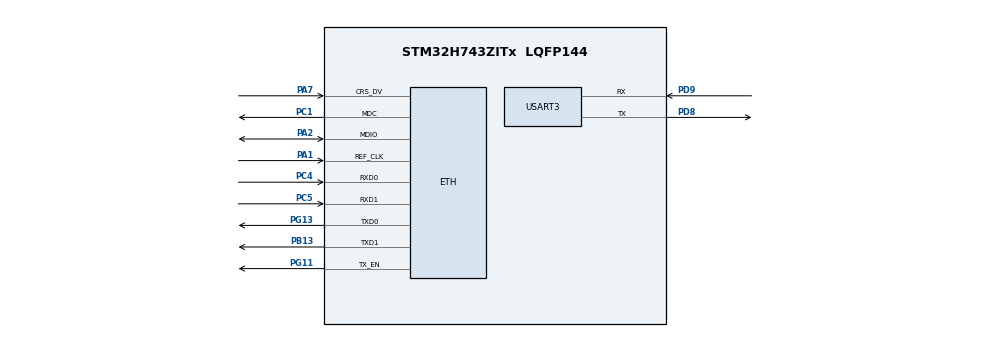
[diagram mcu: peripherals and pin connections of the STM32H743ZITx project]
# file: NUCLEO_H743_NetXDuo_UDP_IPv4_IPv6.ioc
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CORTEX_M7.AccessPermission_S-Cortex_Memory_Protection_Unit_Region1_Settings_S=MPU_REGION_FULL_ACCESS
CORTEX_M7.BaseAddress_S-Cortex_Memory_Protection_Unit_Region1_Settings_S=0x30040000
CORTEX_M7.CPU_DCache=Enabled
CORTEX_M7.CPU_ICache=Enabled
CORTEX_M7.DisableExec_S-Cortex_Memory_Protection_Unit_Region1_Settings_S=MPU_INSTRUCTION_ACCESS_DISABLE
CORTEX_M7.Enable_S-Cortex_Memory_Protection_Unit_Region1_Settings_S=MPU_REGION_ENABLE
CORTEX_M7.Size_S-Cortex_Memory_Protection_Unit_Region1_Settings_S=MPU_REGION_SIZE_128KB
CORTEX_M7.TypeExtField_S-Cortex_Memory_Protection_Unit_Region1_Settings_S=MPU_TEX_LEVEL1
CORTEX_M7.default_mode_Activation=1
ETH.MediaInterface=HAL_ETH_RMII_MODE
ETH.RxDescAddress=0x30040000
ETH.TxDescAddress=0x30040060
Mcu.Family=STM32H7
Mcu.Name=STM32H743ZITx
Mcu.Package=LQFP144
NVIC.ETH_IRQn=true\:0\:0\:false\:false\:true\:false\:true\:true\:true
NVIC.PriorityGroup=NVIC_PRIORITYGROUP_4
NVIC.TIM6_DAC_IRQn=true\:15\:0\:false\:false\:true\:false\:false\:true\:true
NVIC.TimeBase=TIM6_DAC_IRQn
NVIC.TimeBaseIP=TIM6
PA1.GPIO_Speed=GPIO_SPEED_FREQ_VERY_HIGH
PA1.Mode=RMII
PA1.Signal=ETH_REF_CLK
PA2.GPIO_Speed=GPIO_SPEED_FREQ_VERY_HIGH
PA2.Mode=RMII
PA2.Signal=ETH_MDIO
PA7.GPIO_Speed=GPIO_SPEED_FREQ_VERY_HIGH
PA7.Mode=RMII
PA7.Signal=ETH_CRS_DV
PB13.GPIO_Speed=GPIO_SPEED_FREQ_VERY_HIGH
PB13.Mode=RMII
PB13.Signal=ETH_TXD1
PC1.GPIO_Speed=GPIO_SPEED_FREQ_VERY_HIGH
PC1.Mode=RMII
PC1.Signal=ETH_MDC
PC4.GPIO_Speed=GPIO_SPEED_FREQ_VERY_HIGH
PC4.Mode=RMII
PC4.Signal=ETH_RXD0
PC5.GPIO_Speed=GPIO_SPEED_FREQ_VERY_HIGH
PC5.Mode=RMII
PC5.Signal=ETH_RXD1
PD8.Mode=Asynchronous
PD8.Signal=USART3_TX
PD9.Mode=Asynchronous
PD9.Signal=USART3_RX
PG11.GPIO_Speed=GPIO_SPEED_FREQ_VERY_HIGH
PG11.Mode=RMII
PG11.Signal=ETH_TX_EN
PG13.GPIO_Speed=GPIO_SPEED_FREQ_VERY_HIGH
PG13.Mode=RMII
PG13.Signal=ETH_TXD0
PH0-OSC_IN\ (PH0).Mode=HSE-External-Clock-Source
PH0-OSC_IN\ (PH0).Signal=RCC_OSC_IN
ProjectManager.HeapSize=0x200
ProjectManager.StackSize=0x400
ProjectManager.TargetToolchain=STM32CubeIDE
RCC.ADCFreq_Value=16125000
RCC.APB1Freq_Value=100000000
RCC.APB2Freq_Value=100000000
RCC.APB3Freq_Value=100000000
RCC.APB4Freq_Value=100000000
RCC.CortexFreq_Value=400000000
RCC.D1PPRE=RCC_APB3_DIV2
RCC.D2PPRE1=RCC_APB1_DIV2
RCC.D2PPRE2=RCC_APB2_DIV2
RCC.D3PPRE=RCC_APB4_DIV2
RCC.DIVM1=1
RCC.DIVN1=100
RCC.HCLKFreq_Value=200000000
RCC.HPRE=RCC_HCLK_DIV2
RCC.HSE_VALUE=8000000
RCC.PLLFRACN=0
RCC.PLLSourceVirtual=RCC_PLLSOURCE_HSE
RCC.PWR_Regulator_Voltage_Scale=PWR_REGULATOR_VOLTAGE_SCALE1
RCC.SYSCLKFreq_VALUE=400000000
RCC.SYSCLKSource=RCC_SYSCLKSOURCE_PLLCLK
RCC.USBFreq_Value=400000000
STMicroelectronics.X-CUBE-AZRTOS-H7.3.1.0.FEATURE_NX_IPV6=true
STMicroelectronics.X-CUBE-AZRTOS-H7.3.1.0.InterfacesCcNetworkJjEthernetOoInterface=true
STMicroelectronics.X-CUBE-AZRTOS-H7.3.1.0.InterfacesCcNetworkJjEthernetOoPhyOoInterface=LAN8742IiPhyIiInterface
STMicroelectronics.X-CUBE-AZRTOS-H7.3.1.0.NX_APP_IP_INSTANCE_THREAD_SIZE=2*1024
STMicroelectronics.X-CUBE-AZRTOS-H7.3.1.0.NX_APP_MEM_POOL_SIZE=30*1024
STMicroelectronics.X-CUBE-AZRTOS-H7.3.1.0.NX_APP_PACKET_POOL_SIZE=10
STMicroelectronics.X-CUBE-AZRTOS-H7.3.1.0.NX_APP_THREAD_STACK_SIZE=2*1024
STMicroelectronics.X-CUBE-AZRTOS-H7.3.1.0.NetXDuoCcNetworkJjNetXDuoJjNXOoCore=true
STMicroelectronics.X-CUBE-AZRTOS-H7.3.1.0.NetXDuo_Static_IP_address=192.168.1.111
STMicroelectronics.X-CUBE-AZRTOS-H7.3.1.0.STM32CubeIiBSPIiComponentsCcBoardOoPartJjETHPhyJjLAN8742=true
STMicroelectronics.X-CUBE-AZRTOS-H7.3.1.0.ThreadXCcRTOSJjThreadXJjCore=true
STMicroelectronics.X-CUBE-AZRTOS-H7.3.1.0_IsAnAzureRtosMw=true
USART3.VirtualMode-Asynchronous=VM_ASYNC
VP_STMicroelectronics.X-CUBE-AZRTOS-H7_VS_BoardOoPartJjSTM32CubeIiBSPIiComponents_1.1.0_3.1.0.Mode=BoardOoPartJjSTM32CubeIiBSPIiComponents
VP_STMicroelectronics.X-CUBE-AZRTOS-H7_VS_NetworkJjInterfaces_2.1.0_3.1.0.Mode=NetworkJjInterfaces
VP_STMicroelectronics.X-CUBE-AZRTOS-H7_VS_NetworkJjNetXDuo_6.2.0_3.1.0.Mode=NetworkJjNetXDuo
VP_STMicroelectronics.X-CUBE-AZRTOS-H7_VS_RTOSJjThreadX_6.2.0_3.1.0.Mode=RTOSJjThreadX
VP_SYS_VS_tim6.Mode=TIM6
board=NUCLEO-H743ZI2

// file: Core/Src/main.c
/* USER CODE BEGIN Header */
/**
  ******************************************************************************
  * @file           : main.c
  * @brief          : Main program body
  ******************************************************************************
  * @attention
  *
  * Copyright (c) 2023 STMicroelectronics.
  * All rights reserved.
  *
  * This software is licensed under terms that can be found in the LICENSE file
  * in the root directory of this software component.
  * If no LICENSE file comes with this software, it is provided AS-IS.
  *
  ******************************************************************************
  */
/* USER CODE END Header */
#include "app_threadx.h"
#include "main.h"
#include "string.h"

#if defined ( __ICCARM__ ) /*!< IAR Compiler */
#pragma location=0x30040000
ETH_DMADescTypeDef  DMARxDscrTab[ETH_RX_DESC_CNT]; /* Ethernet Rx DMA Descriptors */
#pragma location=0x30040060
ETH_DMADescTypeDef  DMATxDscrTab[ETH_TX_DESC_CNT]; /* Ethernet Tx DMA Descriptors */

#elif defined ( __CC_ARM )  /* MDK ARM Compiler */

__attribute__((at(0x30040000))) ETH_DMADescTypeDef  DMARxDscrTab[ETH_RX_DESC_CNT]; /* Ethernet Rx DMA Descriptors */
__attribute__((at(0x30040060))) ETH_DMADescTypeDef  DMATxDscrTab[ETH_TX_DESC_CNT]; /* Ethernet Tx DMA Descriptors */

#elif defined ( __GNUC__ ) /* GNU Compiler */
ETH_DMADescTypeDef DMARxDscrTab[ETH_RX_DESC_CNT] __attribute__((section(".RxDecripSection"))); /* Ethernet Rx DMA Descriptors */
ETH_DMADescTypeDef DMATxDscrTab[ETH_TX_DESC_CNT] __attribute__((section(".TxDecripSection")));   /* Ethernet Tx DMA Descriptors */

#endif

ETH_TxPacketConfig TxConfig;

ETH_HandleTypeDef heth;

UART_HandleTypeDef huart3;

void SystemClock_Config(void);
static void MPU_Config(void);
static void MX_GPIO_Init(void);
static void MX_ETH_Init(void);
static void MX_USART3_UART_Init(void);

/* USER CODE BEGIN 0 */

int __io_putchar(int ch)
{
  /* Place your implementation of fputc here */
  /* e.g. write a character to the USART1 and Loop until the end of transmission */
  HAL_UART_Transmit(&huart3, (uint8_t *)&ch, 1, 0xFFFF);

  return ch;
}

/* USER CODE END 0 */

int main(void)
{

  /* MPU Configuration--------------------------------------------------------*/
  MPU_Config();

  /* Enable I-Cache---------------------------------------------------------*/
  SCB_EnableICache();

  /* Enable D-Cache---------------------------------------------------------*/
  SCB_EnableDCache();

  /* MCU Configuration--------------------------------------------------------*/

  /* Reset of all peripherals, Initializes the Flash interface and the Systick. */
  HAL_Init();

  /* Configure the system clock */
  SystemClock_Config();

  /* Initialize all configured peripherals */
  MX_GPIO_Init();
  MX_ETH_Init();
  MX_USART3_UART_Init();

  MX_ThreadX_Init();

  /* We should never get here as control is now taken by the scheduler */
  /* Infinite loop */
  while (1)
  {

  }
}

void SystemClock_Config(void)
{
  RCC_OscInitTypeDef RCC_OscInitStruct = {0};
  RCC_ClkInitTypeDef RCC_ClkInitStruct = {0};

  /** Supply configuration update enable
  */
  HAL_PWREx_ConfigSupply(PWR_LDO_SUPPLY);

  /** Configure the main internal regulator output voltage
  */
  __HAL_PWR_VOLTAGESCALING_CONFIG(PWR_REGULATOR_VOLTAGE_SCALE1);

  while(!__HAL_PWR_GET_FLAG(PWR_FLAG_VOSRDY)) {}

  /** Initializes the RCC Oscillators according to the specified parameters
  * in the RCC_OscInitTypeDef structure.
  */
  RCC_OscInitStruct.OscillatorType = RCC_OSCILLATORTYPE_HSE;
  RCC_OscInitStruct.HSEState = RCC_HSE_BYPASS;
  RCC_OscInitStruct.PLL.PLLState = RCC_PLL_ON;
  RCC_OscInitStruct.PLL.PLLSource = RCC_PLLSOURCE_HSE;
  RCC_OscInitStruct.PLL.PLLM = 1;
  RCC_OscInitStruct.PLL.PLLN = 100;
  RCC_OscInitStruct.PLL.PLLP = 2;
  RCC_OscInitStruct.PLL.PLLQ = 2;
  RCC_OscInitStruct.PLL.PLLR = 2;
  RCC_OscInitStruct.PLL.PLLRGE = RCC_PLL1VCIRANGE_3;
  RCC_OscInitStruct.PLL.PLLVCOSEL = RCC_PLL1VCOWIDE;
  RCC_OscInitStruct.PLL.PLLFRACN = 0;
  if (HAL_RCC_OscConfig(&RCC_OscInitStruct) != HAL_OK)
  {
    Error_Handler();
  }

  /** Initializes the CPU, AHB and APB buses clocks
  */
  RCC_ClkInitStruct.ClockType = RCC_CLOCKTYPE_HCLK|RCC_CLOCKTYPE_SYSCLK
                              |RCC_CLOCKTYPE_PCLK1|RCC_CLOCKTYPE_PCLK2
                              |RCC_CLOCKTYPE_D3PCLK1|RCC_CLOCKTYPE_D1PCLK1;
  RCC_ClkInitStruct.SYSCLKSource = RCC_SYSCLKSOURCE_PLLCLK;
  RCC_ClkInitStruct.SYSCLKDivider = RCC_SYSCLK_DIV1;
  RCC_ClkInitStruct.AHBCLKDivider = RCC_HCLK_DIV2;
  RCC_ClkInitStruct.APB3CLKDivider = RCC_APB3_DIV2;
  RCC_ClkInitStruct.APB1CLKDivider = RCC_APB1_DIV2;
  RCC_ClkInitStruct.APB2CLKDivider = RCC_APB2_DIV2;
  RCC_ClkInitStruct.APB4CLKDivider = RCC_APB4_DIV2;

  if (HAL_RCC_ClockConfig(&RCC_ClkInitStruct, FLASH_LATENCY_2) != HAL_OK)
  {
    Error_Handler();
  }
}

static void MX_ETH_Init(void)
{

   static uint8_t MACAddr[6];

  heth.Instance = ETH;
  MACAddr[0] = 0x00;
  MACAddr[1] = 0x80;
  MACAddr[2] = 0xE1;
  MACAddr[3] = 0x00;
  MACAddr[4] = 0x00;
  MACAddr[5] = 0x00;
  heth.Init.MACAddr = &MACAddr[0];
  heth.Init.MediaInterface = HAL_ETH_RMII_MODE;
  heth.Init.TxDesc = DMATxDscrTab;
  heth.Init.RxDesc = DMARxDscrTab;
  heth.Init.RxBuffLen = 1536;

  if (HAL_ETH_Init(&heth) != HAL_OK)
  {
    Error_Handler();
  }

  memset(&TxConfig, 0 , sizeof(ETH_TxPacketConfig));
  TxConfig.Attributes = ETH_TX_PACKETS_FEATURES_CSUM | ETH_TX_PACKETS_FEATURES_CRCPAD;
  TxConfig.ChecksumCtrl = ETH_CHECKSUM_IPHDR_PAYLOAD_INSERT_PHDR_CALC;
  TxConfig.CRCPadCtrl = ETH_CRC_PAD_INSERT;

}

static void MX_USART3_UART_Init(void)
{

  huart3.Instance = USART3;
  huart3.Init.BaudRate = 115200;
  huart3.Init.WordLength = UART_WORDLENGTH_8B;
  huart3.Init.StopBits = UART_STOPBITS_1;
  huart3.Init.Parity = UART_PARITY_NONE;
  huart3.Init.Mode = UART_MODE_TX_RX;
  huart3.Init.HwFlowCtl = UART_HWCONTROL_NONE;
  huart3.Init.OverSampling = UART_OVERSAMPLING_16;
  huart3.Init.OneBitSampling = UART_ONE_BIT_SAMPLE_DISABLE;
  huart3.Init.ClockPrescaler = UART_PRESCALER_DIV1;
  huart3.AdvancedInit.AdvFeatureInit = UART_ADVFEATURE_NO_INIT;
  if (HAL_UART_Init(&huart3) != HAL_OK)
  {
    Error_Handler();
  }
  if (HAL_UARTEx_SetTxFifoThreshold(&huart3, UART_TXFIFO_THRESHOLD_1_8) != HAL_OK)
  {
    Error_Handler();
  }
  if (HAL_UARTEx_SetRxFifoThreshold(&huart3, UART_RXFIFO_THRESHOLD_1_8) != HAL_OK)
  {
    Error_Handler();
  }
  if (HAL_UARTEx_DisableFifoMode(&huart3) != HAL_OK)
  {
    Error_Handler();
  }

}

static void MX_GPIO_Init(void)
{
  GPIO_InitTypeDef GPIO_InitStruct = {0};

  /* GPIO Ports Clock Enable */
  __HAL_RCC_GPIOH_CLK_ENABLE();
  __HAL_RCC_GPIOC_CLK_ENABLE();
  __HAL_RCC_GPIOA_CLK_ENABLE();
  __HAL_RCC_GPIOB_CLK_ENABLE();
  __HAL_RCC_GPIOD_CLK_ENABLE();
  __HAL_RCC_GPIOG_CLK_ENABLE();

  /* Configure GPIO pin Output Level - Set LEDs high initially */
  //HAL_GPIO_WritePin(GPIOB, GPIO_PIN_0 | GPIO_PIN_7 | GPIO_PIN_14, GPIO_PIN_SET);
  HAL_GPIO_WritePin(GPIOB, GPIO_PIN_0 | GPIO_PIN_7 | GPIO_PIN_14, GPIO_PIN_RESET);

  /* Configure GPIO pins for LEDs: LD1 (Green - PB0), LD2 (Blue - PB7), LD3 (Red - PB14) */
  GPIO_InitStruct.Pin = GPIO_PIN_0 | GPIO_PIN_7 | GPIO_PIN_14;
  GPIO_InitStruct.Mode = GPIO_MODE_OUTPUT_PP;
  GPIO_InitStruct.Pull = GPIO_NOPULL;
  GPIO_InitStruct.Speed = GPIO_SPEED_FREQ_LOW;
  HAL_GPIO_Init(GPIOB, &GPIO_InitStruct);

  /* USER CODE BEGIN MX_GPIO_Init 1 */
  /*
   * Custom manual GPIO configuration for B1 Button (PC13) and
   * redundant LED config (LD1/PB0) added by the user.
   * Note: The LD1/PB0 configuration below is redundant as PB0 is already configured above.
   */

  /* Configure GPIO pin : B1_Pin (PC13) for Input */
  GPIO_InitStruct.Pin = B1_Pin;
  GPIO_InitStruct.Mode = GPIO_MODE_INPUT;
  GPIO_InitStruct.Pull = GPIO_NOPULL;
  HAL_GPIO_Init(GPIOC, &GPIO_InitStruct);

  /* Configure GPIO pin : LD1_Pin (PB0) - Redundant with configuration above */
 // GPIO_InitStruct.Pin = LD1_Pin;
 // GPIO_InitStruct.Mode = GPIO_MODE_OUTPUT_PP;
  //GPIO_InitStruct.Pull = GPIO_NOPULL;
  //GPIO_InitStruct.Speed = GPIO_SPEED_FREQ_LOW;
  //HAL_GPIO_Init(GPIOB, &GPIO_InitStruct);

  /* Set initial level for LD1/PB0 - Redundant with HAL_GPIO_WritePin above */
 // HAL_GPIO_WritePin(GPIOB, GPIO_PIN_0, GPIO_PIN_RESET);
  /* USER CODE END MX_GPIO_Init 1 */
}

/* MPU Configuration */

void MPU_Config(void)
{
  MPU_Region_InitTypeDef MPU_InitStruct = {0};

  /* Disables the MPU */
  HAL_MPU_Disable();

  /** Initializes and configures the Region and the memory to be protected
  */
  MPU_InitStruct.Enable = MPU_REGION_ENABLE;
  MPU_InitStruct.Number = MPU_REGION_NUMBER0;
  MPU_InitStruct.BaseAddress = 0x0;
  MPU_InitStruct.Size = MPU_REGION_SIZE_4GB;
  MPU_InitStruct.SubRegionDisable = 0x87;
  MPU_InitStruct.TypeExtField = MPU_TEX_LEVEL0;
  MPU_InitStruct.AccessPermission = MPU_REGION_NO_ACCESS;
  MPU_InitStruct.DisableExec = MPU_INSTRUCTION_ACCESS_DISABLE;
  MPU_InitStruct.IsShareable = MPU_ACCESS_SHAREABLE;
  MPU_InitStruct.IsCacheable = MPU_ACCESS_NOT_CACHEABLE;
  MPU_InitStruct.IsBufferable = MPU_ACCESS_NOT_BUFFERABLE;

  HAL_MPU_ConfigRegion(&MPU_InitStruct);

  /** Initializes and configures the Region and the memory to be protected
  */
  MPU_InitStruct.Number = MPU_REGION_NUMBER1;
  MPU_InitStruct.BaseAddress = 0x30040000;
  MPU_InitStruct.Size = MPU_REGION_SIZE_128KB;
  MPU_InitStruct.SubRegionDisable = 0x0;
  MPU_InitStruct.TypeExtField = MPU_TEX_LEVEL1;
  MPU_InitStruct.AccessPermission = MPU_REGION_FULL_ACCESS;
  MPU_InitStruct.IsShareable = MPU_ACCESS_NOT_SHAREABLE;

  HAL_MPU_ConfigRegion(&MPU_InitStruct);
  /* Enables the MPU */
  HAL_MPU_Enable(MPU_PRIVILEGED_DEFAULT);

}

void HAL_TIM_PeriodElapsedCallback(TIM_HandleTypeDef *htim)
{
  if (htim->Instance == TIM6) {
    HAL_IncTick();
  }
}

void Error_Handler(void)
{
  __disable_irq();
  while (1)
  {
  }
}
